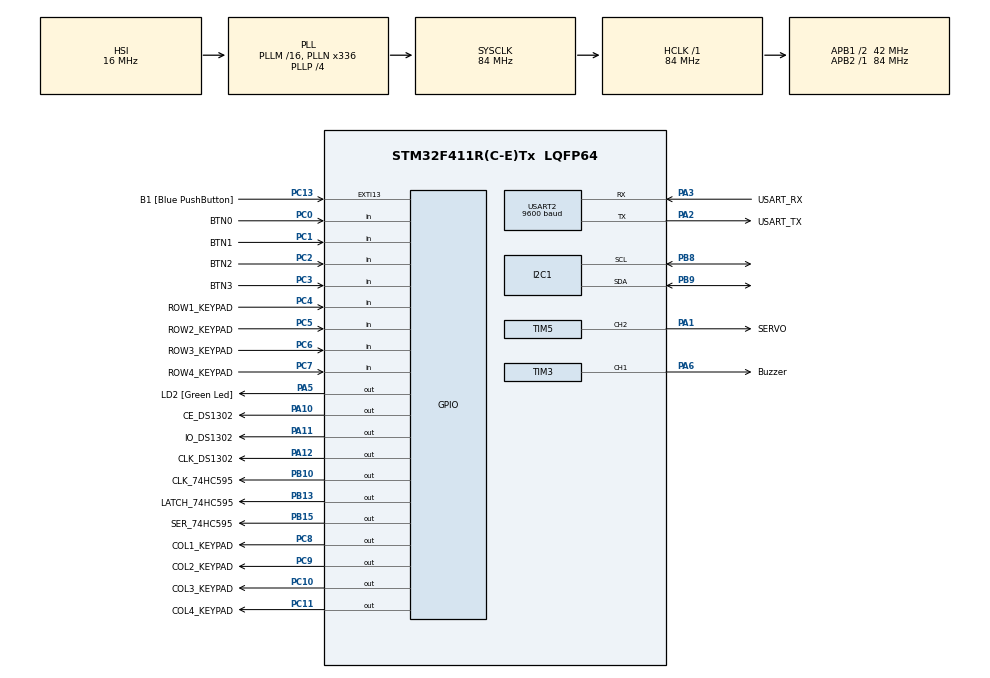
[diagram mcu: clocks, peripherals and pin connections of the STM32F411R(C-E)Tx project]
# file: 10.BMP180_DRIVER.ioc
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FREERTOS.Tasks01=defaultTask,24,128,StartDefaultTask,Default,NULL,Dynamic,NULL,NULL;myTask02,8,128,StartTask02,Default,NULL,Dynamic,NULL,NULL;myTask03,8,128,StartTask03,Default,NULL,Dynamic,NULL,NULL
FREERTOS.configUSE_NEWLIB_REENTRANT=1
Mcu.Family=STM32F4
Mcu.Name=STM32F411R(C-E)Tx
Mcu.Package=LQFP64
NVIC.PriorityGroup=NVIC_PRIORITYGROUP_4
NVIC.TIM1_TRG_COM_TIM11_IRQn=true\:5\:0\:false\:false\:true\:true\:true\:true
NVIC.TIM1_UP_TIM10_IRQn=true\:15\:0\:false\:false\:true\:false\:false\:true
NVIC.TIM3_IRQn=true\:5\:0\:false\:false\:true\:true\:true\:true
NVIC.TIM5_IRQn=true\:5\:0\:false\:false\:true\:true\:true\:true
NVIC.TimeBase=TIM1_UP_TIM10_IRQn
NVIC.TimeBaseIP=TIM10
NVIC.USART2_IRQn=true\:5\:0\:false\:false\:true\:true\:true\:true
PA1.GPIO_Label=SERVO
PA1.Signal=S_TIM5_CH2
PA10.GPIO_Label=CE_DS1302
PA10.Signal=GPIO_Output
PA11.GPIO_Label=IO_DS1302
PA11.Signal=GPIO_Output
PA12.GPIO_Label=CLK_DS1302
PA12.Signal=GPIO_Output
PA13.GPIO_Label=TMS
PA13.Mode=Serial_Wire
PA13.Signal=SYS_JTMS-SWDIO
PA14.GPIO_Label=TCK
PA14.Mode=Serial_Wire
PA14.Signal=SYS_JTCK-SWCLK
PA2.GPIO_Label=USART_TX
PA2.Mode=Asynchronous
PA2.Signal=USART2_TX
PA3.GPIO_Label=USART_RX
PA3.Mode=Asynchronous
PA3.Signal=USART2_RX
PA5.GPIO_Label=LD2 [Green Led]
PA5.Signal=GPIO_Output
PA6.GPIO_Label=Buzzer
PA6.Signal=S_TIM3_CH1
PB10.GPIO_Label=CLK_74HC595
PB10.Signal=GPIO_Output
PB13.GPIO_Label=LATCH_74HC595
PB13.Signal=GPIO_Output
PB15.GPIO_Label=SER_74HC595
PB15.Signal=GPIO_Output
PB8.GPIO_Pu=GPIO_PULLUP
PB8.Mode=I2C
PB8.Signal=I2C1_SCL
PB9.GPIO_Pu=GPIO_PULLUP
PB9.Mode=I2C
PB9.Signal=I2C1_SDA
PC0.GPIO_Label=BTN0
PC0.Signal=GPIO_Input
PC1.GPIO_Label=BTN1
PC1.Signal=GPIO_Input
PC10.GPIO_Label=COL3_KEYPAD
PC10.Signal=GPIO_Output
PC11.GPIO_Label=COL4_KEYPAD
PC11.Signal=GPIO_Output
PC13-ANTI_TAMP.GPIO_Label=B1 [Blue PushButton]
PC13-ANTI_TAMP.GPIO_ModeDefaultEXTI=GPIO_MODE_IT_FALLING
PC13-ANTI_TAMP.Signal=GPXTI13
PC14-OSC32_IN.Mode=LSE-External-Oscillator
PC14-OSC32_IN.Signal=RCC_OSC32_IN
PC15-OSC32_OUT.Mode=LSE-External-Oscillator
PC15-OSC32_OUT.Signal=RCC_OSC32_OUT
PC2.GPIO_Label=BTN2
PC2.Signal=GPIO_Input
PC3.GPIO_Label=BTN3
PC3.Signal=GPIO_Input
PC4.GPIO_Label=ROW1_KEYPAD
PC4.GPIO_PuPd=GPIO_PULLUP
PC4.Signal=GPIO_Input
PC5.GPIO_Label=ROW2_KEYPAD
PC5.GPIO_PuPd=GPIO_PULLUP
PC5.Signal=GPIO_Input
PC6.GPIO_Label=ROW3_KEYPAD
PC6.GPIO_PuPd=GPIO_PULLUP
PC6.Signal=GPIO_Input
PC7.GPIO_Label=ROW4_KEYPAD
PC7.GPIO_PuPd=GPIO_PULLUP
PC7.Signal=GPIO_Input
PC8.GPIO_Label=COL1_KEYPAD
PC8.Signal=GPIO_Output
PC9.GPIO_Label=COL2_KEYPAD
PC9.Signal=GPIO_Output
PH0\ -\ OSC_IN.Mode=HSE-External-Clock-Source
PH0\ -\ OSC_IN.Signal=RCC_OSC_IN
PH1\ -\ OSC_OUT.Mode=HSE-External-Clock-Source
PH1\ -\ OSC_OUT.Signal=RCC_OSC_OUT
ProjectManager.HeapSize=0x200
ProjectManager.StackSize=0x400
ProjectManager.TargetToolchain=STM32CubeIDE
RCC.48MHZClocksFreq_Value=84000000
RCC.AHBFreq_Value=84000000
RCC.APB1CLKDivider=RCC_HCLK_DIV2
RCC.APB1Freq_Value=42000000
RCC.APB1TimFreq_Value=84000000
RCC.APB2Freq_Value=84000000
RCC.APB2TimFreq_Value=84000000
RCC.CortexFreq_Value=84000000
RCC.FLatency-AdvancedSettings=FLASH_LATENCY_2
RCC.HCLKFreq_Value=84000000
RCC.HSE_VALUE=8000000
RCC.HSI_VALUE=16000000
RCC.PLLN=336
RCC.PLLP=RCC_PLLP_DIV4
RCC.SYSCLKFreq_VALUE=84000000
RCC.SYSCLKSource=RCC_SYSCLKSOURCE_PLLCLK
RCC.VCOOutputFreq_Value=336000000
SH.S_TIM3_CH1.0=TIM3_CH1,PWM Generation1 CH1
SH.S_TIM5_CH2.0=TIM5_CH2,PWM Generation2 CH2
TIM11.Period=1000-1
TIM11.Prescaler=84-1
TIM2.Prescaler=84-1
TIM3.Channel-PWM\ Generation1\ CH1=TIM_CHANNEL_1
TIM3.Period=400-1
TIM3.Prescaler=52.5-1
TIM3.Pulse-PWM\ Generation1\ CH1=200-1
TIM5.Channel-PWM\ Generation2\ CH2=TIM_CHANNEL_2
TIM5.Period=1000-1
TIM5.Prescaler=1680-1
USART2.BaudRate=9600
USART2.VirtualMode=VM_ASYNC
VP_FREERTOS_VS_CMSIS_V2.Mode=CMSIS_V2
VP_SYS_VS_tim10.Mode=TIM10
VP_TIM11_VS_ClockSourceINT.Mode=Enable_Timer
VP_TIM2_VS_ClockSourceINT.Mode=Internal
VP_TIM3_VS_ClockSourceINT.Mode=Internal
VP_TIM5_VS_ClockSourceINT.Mode=Internal
board=NUCLEO-F411RE

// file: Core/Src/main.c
/* USER CODE BEGIN Header */
/**
  ******************************************************************************
  * @file           : main.c
  * @brief          : Main program body
  ******************************************************************************
  * @attention
  *
  * <h2><center>&copy; Copyright (c) 2025 STMicroelectronics.
  * All rights reserved.</center></h2>
  *
  * This software component is licensed by ST under BSD 3-Clause license,
  * the "License"; You may not use this file except in compliance with the
  * License. You may obtain a copy of the License at:
  *                        opensource.org/licenses/BSD-3-Clause
  *
  ******************************************************************************
  */
/* USER CODE END Header */
#include "main.h"
#include "cmsis_os.h"

/* USER CODE BEGIN Includes */
#include "extern.h"
#include "bmp180.h"
/* USER CODE END Includes */

I2C_HandleTypeDef hi2c1;

TIM_HandleTypeDef htim2;
TIM_HandleTypeDef htim3;
TIM_HandleTypeDef htim5;
TIM_HandleTypeDef htim11;

UART_HandleTypeDef huart2;

/* Definitions for defaultTask */
osThreadId_t defaultTaskHandle;
const osThreadAttr_t defaultTask_attributes = {
  .name = "defaultTask",
  .stack_size = 128 * 4,
  .priority = (osPriority_t) osPriorityNormal,
};
/* Definitions for myTask02 */
osThreadId_t myTask02Handle;
const osThreadAttr_t myTask02_attributes = {
  .name = "myTask02",
  .stack_size = 128 * 4,
  .priority = (osPriority_t) osPriorityLow,
};
/* Definitions for myTask03 */
osThreadId_t myTask03Handle;
const osThreadAttr_t myTask03_attributes = {
  .name = "myTask03",
  .stack_size = 128 * 4,
  .priority = (osPriority_t) osPriorityLow,
};
/* USER CODE BEGIN PV */
uint8_t rx_data; //uart2 rx byte
volatile int TIM11_1ms_counter = 0;
volatile int TIM11_1ms_counter2 = 0;
volatile int TIM11_keypad_scan_timer = 0;
BMP180_get_cal_param bmp;

/* USER CODE END PV */

void SystemClock_Config(void);
static void MX_GPIO_Init(void);
static void MX_USART2_UART_Init(void);
static void MX_TIM11_Init(void);
static void MX_TIM2_Init(void);
static void MX_I2C1_Init(void);
static void MX_TIM3_Init(void);
static void MX_TIM5_Init(void);
void StartDefaultTask(void *argument);
void StartTask02(void *argument);
void StartTask03(void *argument);

/* USER CODE BEGIN 0 */

#ifdef __GNUC__    // Add for printf
/* With GCC, small printf (option LD Linker->Libraries->Small printf
   set to 'Yes') calls __io_putchar() */
#define PUTCHAR_PROTOTYPE int __io_putchar(int ch)
#else
#define PUTCHAR_PROTOTYPE int fputc(int ch, FILE *f)
#endif /* __GNUC__ */
/**
  * @brief  Retargets the C library printf function to the USART.
  * @param  None
  * @retval None
  */
PUTCHAR_PROTOTYPE   // Add for printf
{
  /* Place your implementation of fputc here */
  /* e.g. write a character to the USART3 and Loop until the end of transmission */
  HAL_UART_Transmit(&huart2, (uint8_t *)&ch, 1, 0xFFFF);

  return ch;
}
/* USER CODE END 0 */

int main(void)
{

  /* MCU Configuration--------------------------------------------------------*/

  /* Reset of all peripherals, Initializes the Flash interface and the Systick. */
  HAL_Init();

  /* Configure the system clock */
  SystemClock_Config();

  /* Initialize all configured peripherals */
  MX_GPIO_Init();
  MX_USART2_UART_Init();
  MX_TIM11_Init();
  MX_TIM2_Init();
  MX_I2C1_Init();
  MX_TIM3_Init();
  MX_TIM5_Init();
  /* USER CODE BEGIN 2 */
  HAL_UART_Receive_IT(&huart2, &rx_data, 1);
  HAL_TIM_Base_Start_IT(&htim11);
  HAL_TIM_Base_Start_IT(&htim2);  //for make delay_us

  //keypadInit();

//  if (HAL_I2C_IsDeviceReady(&hi2c1, 0xEE, 3, 100) == HAL_OK) {
//      printf("BMP180 detected at 0x77\n");
//  } else if (HAL_I2C_IsDeviceReady(&hi2c1, 0xEC, 3, 100) == HAL_OK) {
//      printf("BMP180 detected at 0x76\n");
//  } else {
//      printf("BMP180 not detected!\n");
//  }

   if (BMP180_init(&bmp) != HAL_OK)
   {
       Error_Handler();
   }

   while(1)
   {
    	if(BMP180_read_temp(&bmp) == HAL_OK)
    	{
    		printf("Temp = %1.fC\n", (float)bmp.temp);
    	}

    	if(BMP180_read_pres(&bmp) == HAL_OK)
		{
    		printf("Pres = %2.fhPa\n", (float)bmp.pres);
		}

    	HAL_Delay(1000);
    }

//      if (BMP180_ReadTemperature(&hbmp180) == HAL_OK)
//      {
//          temperature = BMP180_GetTemperature(&hbmp180);
//          printf("Temperature: %.1f°C\r\n", temperature);
//      }
//
//      // ?��?�� ?���?
//      if (BMP180_ReadPressure(&hbmp180) == HAL_OK)
//      {
//          pressure = BMP180_GetPressure(&hbmp180);
//          printf("Pressure: %.2f hPa\r\n", pressure);
//      }
//
//      HAL_Delay(1000); // 1�? ??�?
//  }
  //dotmatrix_main_func();
  //dotmatrix_main_test();
  //led_main();
  //i2c_lcd_main();
  //ds1302_main();
  //buzzer_main();
  //servo_motor_main();

  /* USER CODE END 2 */

  /* Init scheduler */
  osKernelInitialize();

  /* Create the thread(s) */
  /* creation of defaultTask */
  defaultTaskHandle = osThreadNew(StartDefaultTask, NULL, &defaultTask_attributes);

  /* creation of myTask02 */
  myTask02Handle = osThreadNew(StartTask02, NULL, &myTask02_attributes);

  /* creation of myTask03 */
  myTask03Handle = osThreadNew(StartTask03, NULL, &myTask03_attributes);

  /* Start scheduler */
  osKernelStart();

  /* We should never get here as control is now taken by the scheduler */
  /* Infinite loop */
  /* USER CODE BEGIN WHILE */
  while (1)
  {
	  button_led_toggle_test();
    /* USER CODE END WHILE */

  }
}

void SystemClock_Config(void)
{
  RCC_OscInitTypeDef RCC_OscInitStruct = {0};
  RCC_ClkInitTypeDef RCC_ClkInitStruct = {0};

  /** Configure the main internal regulator output voltage
  */
  __HAL_RCC_PWR_CLK_ENABLE();
  __HAL_PWR_VOLTAGESCALING_CONFIG(PWR_REGULATOR_VOLTAGE_SCALE1);
  /** Initializes the RCC Oscillators according to the specified parameters
  * in the RCC_OscInitTypeDef structure.
  */
  RCC_OscInitStruct.OscillatorType = RCC_OSCILLATORTYPE_HSI;
  RCC_OscInitStruct.HSIState = RCC_HSI_ON;
  RCC_OscInitStruct.HSICalibrationValue = RCC_HSICALIBRATION_DEFAULT;
  RCC_OscInitStruct.PLL.PLLState = RCC_PLL_ON;
  RCC_OscInitStruct.PLL.PLLSource = RCC_PLLSOURCE_HSI;
  RCC_OscInitStruct.PLL.PLLM = 16;
  RCC_OscInitStruct.PLL.PLLN = 336;
  RCC_OscInitStruct.PLL.PLLP = RCC_PLLP_DIV4;
  RCC_OscInitStruct.PLL.PLLQ = 4;
  if (HAL_RCC_OscConfig(&RCC_OscInitStruct) != HAL_OK)
  {
    Error_Handler();
  }
  /** Initializes the CPU, AHB and APB buses clocks
  */
  RCC_ClkInitStruct.ClockType = RCC_CLOCKTYPE_HCLK|RCC_CLOCKTYPE_SYSCLK
                              |RCC_CLOCKTYPE_PCLK1|RCC_CLOCKTYPE_PCLK2;
  RCC_ClkInitStruct.SYSCLKSource = RCC_SYSCLKSOURCE_PLLCLK;
  RCC_ClkInitStruct.AHBCLKDivider = RCC_SYSCLK_DIV1;
  RCC_ClkInitStruct.APB1CLKDivider = RCC_HCLK_DIV2;
  RCC_ClkInitStruct.APB2CLKDivider = RCC_HCLK_DIV1;

  if (HAL_RCC_ClockConfig(&RCC_ClkInitStruct, FLASH_LATENCY_2) != HAL_OK)
  {
    Error_Handler();
  }
}

static void MX_I2C1_Init(void)
{

  hi2c1.Instance = I2C1;
  hi2c1.Init.ClockSpeed = 100000;
  hi2c1.Init.DutyCycle = I2C_DUTYCYCLE_2;
  hi2c1.Init.OwnAddress1 = 0;
  hi2c1.Init.AddressingMode = I2C_ADDRESSINGMODE_7BIT;
  hi2c1.Init.DualAddressMode = I2C_DUALADDRESS_DISABLE;
  hi2c1.Init.OwnAddress2 = 0;
  hi2c1.Init.GeneralCallMode = I2C_GENERALCALL_DISABLE;
  hi2c1.Init.NoStretchMode = I2C_NOSTRETCH_DISABLE;
  if (HAL_I2C_Init(&hi2c1) != HAL_OK)
  {
    Error_Handler();
  }

}

static void MX_TIM2_Init(void)
{

  TIM_ClockConfigTypeDef sClockSourceConfig = {0};
  TIM_MasterConfigTypeDef sMasterConfig = {0};

  htim2.Instance = TIM2;
  htim2.Init.Prescaler = 84-1;
  htim2.Init.CounterMode = TIM_COUNTERMODE_UP;
  htim2.Init.Period = 4294967295;
  htim2.Init.ClockDivision = TIM_CLOCKDIVISION_DIV1;
  htim2.Init.AutoReloadPreload = TIM_AUTORELOAD_PRELOAD_DISABLE;
  if (HAL_TIM_Base_Init(&htim2) != HAL_OK)
  {
    Error_Handler();
  }
  sClockSourceConfig.ClockSource = TIM_CLOCKSOURCE_INTERNAL;
  if (HAL_TIM_ConfigClockSource(&htim2, &sClockSourceConfig) != HAL_OK)
  {
    Error_Handler();
  }
  sMasterConfig.MasterOutputTrigger = TIM_TRGO_RESET;
  sMasterConfig.MasterSlaveMode = TIM_MASTERSLAVEMODE_DISABLE;
  if (HAL_TIMEx_MasterConfigSynchronization(&htim2, &sMasterConfig) != HAL_OK)
  {
    Error_Handler();
  }

}

static void MX_TIM3_Init(void)
{

  TIM_ClockConfigTypeDef sClockSourceConfig = {0};
  TIM_MasterConfigTypeDef sMasterConfig = {0};
  TIM_OC_InitTypeDef sConfigOC = {0};

  htim3.Instance = TIM3;
  htim3.Init.Prescaler = 52.5-1;
  htim3.Init.CounterMode = TIM_COUNTERMODE_UP;
  htim3.Init.Period = 400-1;
  htim3.Init.ClockDivision = TIM_CLOCKDIVISION_DIV1;
  htim3.Init.AutoReloadPreload = TIM_AUTORELOAD_PRELOAD_DISABLE;
  if (HAL_TIM_Base_Init(&htim3) != HAL_OK)
  {
    Error_Handler();
  }
  sClockSourceConfig.ClockSource = TIM_CLOCKSOURCE_INTERNAL;
  if (HAL_TIM_ConfigClockSource(&htim3, &sClockSourceConfig) != HAL_OK)
  {
    Error_Handler();
  }
  if (HAL_TIM_PWM_Init(&htim3) != HAL_OK)
  {
    Error_Handler();
  }
  sMasterConfig.MasterOutputTrigger = TIM_TRGO_RESET;
  sMasterConfig.MasterSlaveMode = TIM_MASTERSLAVEMODE_DISABLE;
  if (HAL_TIMEx_MasterConfigSynchronization(&htim3, &sMasterConfig) != HAL_OK)
  {
    Error_Handler();
  }
  sConfigOC.OCMode = TIM_OCMODE_PWM1;
  sConfigOC.Pulse = 200-1;
  sConfigOC.OCPolarity = TIM_OCPOLARITY_HIGH;
  sConfigOC.OCFastMode = TIM_OCFAST_DISABLE;
  if (HAL_TIM_PWM_ConfigChannel(&htim3, &sConfigOC, TIM_CHANNEL_1) != HAL_OK)
  {
    Error_Handler();
  }
  HAL_TIM_MspPostInit(&htim3);

}

static void MX_TIM5_Init(void)
{

  TIM_ClockConfigTypeDef sClockSourceConfig = {0};
  TIM_MasterConfigTypeDef sMasterConfig = {0};
  TIM_OC_InitTypeDef sConfigOC = {0};

  htim5.Instance = TIM5;
  htim5.Init.Prescaler = 1680-1;
  htim5.Init.CounterMode = TIM_COUNTERMODE_UP;
  htim5.Init.Period = 1000-1;
  htim5.Init.ClockDivision = TIM_CLOCKDIVISION_DIV1;
  htim5.Init.AutoReloadPreload = TIM_AUTORELOAD_PRELOAD_DISABLE;
  if (HAL_TIM_Base_Init(&htim5) != HAL_OK)
  {
    Error_Handler();
  }
  sClockSourceConfig.ClockSource = TIM_CLOCKSOURCE_INTERNAL;
  if (HAL_TIM_ConfigClockSource(&htim5, &sClockSourceConfig) != HAL_OK)
  {
    Error_Handler();
  }
  if (HAL_TIM_PWM_Init(&htim5) != HAL_OK)
  {
    Error_Handler();
  }
  sMasterConfig.MasterOutputTrigger = TIM_TRGO_RESET;
  sMasterConfig.MasterSlaveMode = TIM_MASTERSLAVEMODE_DISABLE;
  if (HAL_TIMEx_MasterConfigSynchronization(&htim5, &sMasterConfig) != HAL_OK)
  {
    Error_Handler();
  }
  sConfigOC.OCMode = TIM_OCMODE_PWM1;
  sConfigOC.Pulse = 0;
  sConfigOC.OCPolarity = TIM_OCPOLARITY_HIGH;
  sConfigOC.OCFastMode = TIM_OCFAST_DISABLE;
  if (HAL_TIM_PWM_ConfigChannel(&htim5, &sConfigOC, TIM_CHANNEL_2) != HAL_OK)
  {
    Error_Handler();
  }
  HAL_TIM_MspPostInit(&htim5);

}

static void MX_TIM11_Init(void)
{

  htim11.Instance = TIM11;
  htim11.Init.Prescaler = 84-1;
  htim11.Init.CounterMode = TIM_COUNTERMODE_UP;
  htim11.Init.Period = 1000-1;
  htim11.Init.ClockDivision = TIM_CLOCKDIVISION_DIV1;
  htim11.Init.AutoReloadPreload = TIM_AUTORELOAD_PRELOAD_DISABLE;
  if (HAL_TIM_Base_Init(&htim11) != HAL_OK)
  {
    Error_Handler();
  }

}

static void MX_USART2_UART_Init(void)
{

  huart2.Instance = USART2;
  huart2.Init.BaudRate = 9600;
  huart2.Init.WordLength = UART_WORDLENGTH_8B;
  huart2.Init.StopBits = UART_STOPBITS_1;
  huart2.Init.Parity = UART_PARITY_NONE;
  huart2.Init.Mode = UART_MODE_TX_RX;
  huart2.Init.HwFlowCtl = UART_HWCONTROL_NONE;
  huart2.Init.OverSampling = UART_OVERSAMPLING_16;
  if (HAL_UART_Init(&huart2) != HAL_OK)
  {
    Error_Handler();
  }

}

static void MX_GPIO_Init(void)
{
  GPIO_InitTypeDef GPIO_InitStruct = {0};

  /* GPIO Ports Clock Enable */
  __HAL_RCC_GPIOC_CLK_ENABLE();
  __HAL_RCC_GPIOH_CLK_ENABLE();
  __HAL_RCC_GPIOA_CLK_ENABLE();
  __HAL_RCC_GPIOB_CLK_ENABLE();

  /*Configure GPIO pin Output Level */
  HAL_GPIO_WritePin(GPIOA, LD2_Pin|CE_DS1302_Pin|IO_DS1302_Pin|CLK_DS1302_Pin, GPIO_PIN_RESET);

  /*Configure GPIO pin Output Level */
  HAL_GPIO_WritePin(GPIOB, LCD_RS_Pin|LCD_RW_Pin|LCD_EN_Pin|CLK_74HC595_Pin
                          |LATCH_74HC595_Pin|SER_74HC595_Pin|LCD_D4_Pin|LCD_D5_Pin
                          |LCD_D6_Pin|LCD_D7_Pin, GPIO_PIN_RESET);

  /*Configure GPIO pin Output Level */
  HAL_GPIO_WritePin(GPIOC, COL1_KEYPAD_Pin|COL2_KEYPAD_Pin|COL3_KEYPAD_Pin|COL4_KEYPAD_Pin, GPIO_PIN_RESET);

  /*Configure GPIO pin : B1_Pin */
  GPIO_InitStruct.Pin = B1_Pin;
  GPIO_InitStruct.Mode = GPIO_MODE_IT_FALLING;
  GPIO_InitStruct.Pull = GPIO_NOPULL;
  HAL_GPIO_Init(B1_GPIO_Port, &GPIO_InitStruct);

  /*Configure GPIO pins : BTN0_Pin BTN1_Pin BTN2_Pin BTN3_Pin */
  GPIO_InitStruct.Pin = BTN0_Pin|BTN1_Pin|BTN2_Pin|BTN3_Pin;
  GPIO_InitStruct.Mode = GPIO_MODE_INPUT;
  GPIO_InitStruct.Pull = GPIO_NOPULL;
  HAL_GPIO_Init(GPIOC, &GPIO_InitStruct);

  /*Configure GPIO pins : LD2_Pin CE_DS1302_Pin IO_DS1302_Pin CLK_DS1302_Pin */
  GPIO_InitStruct.Pin = LD2_Pin|CE_DS1302_Pin|IO_DS1302_Pin|CLK_DS1302_Pin;
  GPIO_InitStruct.Mode = GPIO_MODE_OUTPUT_PP;
  GPIO_InitStruct.Pull = GPIO_NOPULL;
  GPIO_InitStruct.Speed = GPIO_SPEED_FREQ_LOW;
  HAL_GPIO_Init(GPIOA, &GPIO_InitStruct);

  /*Configure GPIO pins : ROW1_KEYPAD_Pin ROW2_KEYPAD_Pin ROW3_KEYPAD_Pin ROW4_KEYPAD_Pin */
  GPIO_InitStruct.Pin = ROW1_KEYPAD_Pin|ROW2_KEYPAD_Pin|ROW3_KEYPAD_Pin|ROW4_KEYPAD_Pin;
  GPIO_InitStruct.Mode = GPIO_MODE_INPUT;
  GPIO_InitStruct.Pull = GPIO_PULLUP;
  HAL_GPIO_Init(GPIOC, &GPIO_InitStruct);

  /*Configure GPIO pins : LCD_RS_Pin LCD_RW_Pin LCD_EN_Pin CLK_74HC595_Pin
                           LATCH_74HC595_Pin SER_74HC595_Pin LCD_D4_Pin LCD_D5_Pin
                           LCD_D6_Pin LCD_D7_Pin */
  GPIO_InitStruct.Pin = LCD_RS_Pin|LCD_RW_Pin|LCD_EN_Pin|CLK_74HC595_Pin
                          |LATCH_74HC595_Pin|SER_74HC595_Pin|LCD_D4_Pin|LCD_D5_Pin
                          |LCD_D6_Pin|LCD_D7_Pin;
  GPIO_InitStruct.Mode = GPIO_MODE_OUTPUT_PP;
  GPIO_InitStruct.Pull = GPIO_NOPULL;
  GPIO_InitStruct.Speed = GPIO_SPEED_FREQ_LOW;
  HAL_GPIO_Init(GPIOB, &GPIO_InitStruct);

  /*Configure GPIO pins : COL1_KEYPAD_Pin COL2_KEYPAD_Pin COL3_KEYPAD_Pin COL4_KEYPAD_Pin */
  GPIO_InitStruct.Pin = COL1_KEYPAD_Pin|COL2_KEYPAD_Pin|COL3_KEYPAD_Pin|COL4_KEYPAD_Pin;
  GPIO_InitStruct.Mode = GPIO_MODE_OUTPUT_PP;
  GPIO_InitStruct.Pull = GPIO_NOPULL;
  GPIO_InitStruct.Speed = GPIO_SPEED_FREQ_LOW;
  HAL_GPIO_Init(GPIOC, &GPIO_InitStruct);

}

void StartDefaultTask(void *argument)
{
  /* USER CODE BEGIN 5 */
  /* Infinite loop */
  for(;;)
  {
    HAL_GPIO_TogglePin(GPIOA, GPIO_PIN_5);
    osDelay(50);
  }
  /* USER CODE END 5 */
}

void StartTask02(void *argument)
{
  /* USER CODE BEGIN StartTask02 */
  /* Infinite loop */
  for(;;)
  {
	button_led_toggle_test();
    osDelay(1);
  }
  /* USER CODE END StartTask02 */
}

void StartTask03(void *argument)
{
  for(;;)
  {
	  osDelay(1);
  }
}

void HAL_TIM_PeriodElapsedCallback(TIM_HandleTypeDef *htim)
{
  if (htim->Instance == TIM10) {
    HAL_IncTick();
  }
  /* USER CODE BEGIN Callback 1 */
  if (htim->Instance == TIM11) {
	  TIM11_1ms_counter++;
	  TIM11_1ms_counter2++;
	  TIM11_keypad_scan_timer++;
	  if(TIM11_keypad_scan_timer > 60)
	  {
		  unsigned char key_value;

		  TIM11_keypad_scan_timer = 0;
		  key_value = keypadScan();
		  if(key_value)
		  {
			  insert_queue(key_value);
		  }
	  }
  }
  /* USER CODE END Callback 1 */
}

void Error_Handler(void)
{
  __disable_irq();
  while (1)
  {
  }
}

/************************ (C) COPYRIGHT STMicroelectronics *****END OF FILE****/
